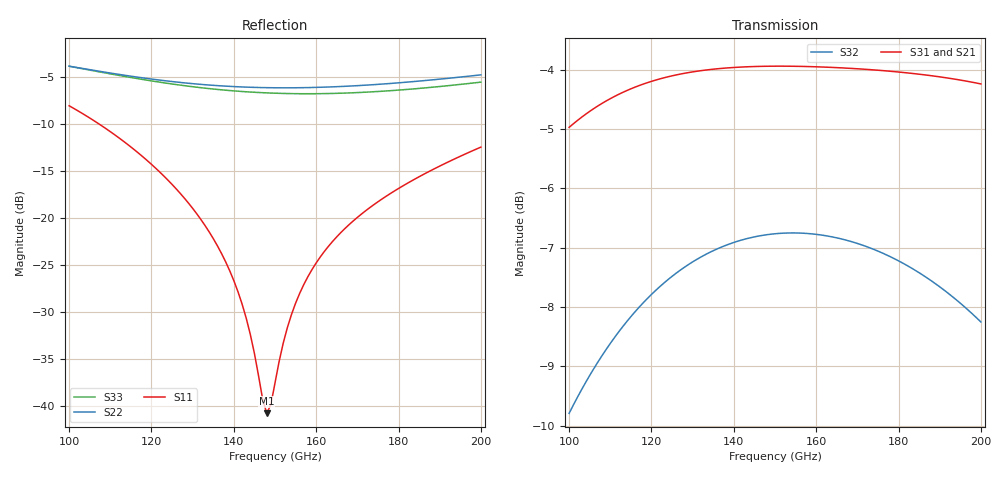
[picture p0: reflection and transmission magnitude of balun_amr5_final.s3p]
! Created with skrf 2.2.0 (http://scikit-rf.org).
# GHz S DB R 50.0
! Port[1] = P1
! Port[2] = P2
! Port[3] = P3
!freq dBS11 angS11 dBS12 angS12 dBS13 angS13
! dBS21 angS21 dBS22 angS22 dBS23 angS23
! dBS31 angS31 dBS32 angS32 dBS33 angS33
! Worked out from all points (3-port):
!   101 points, 100 GHz to 200 GHz, reference 50 ohm
!   strongest paths, dB at 100 GHz, 125 GHz, 150 GHz, 175 GHz, 200 GHz:
!     S31: -5.0, -4.1, -3.9, -4.0, -4.2
!     S21: -4.7, -4.0, -3.9, -4.2, -4.6
!     S32: -9.8, -7.5, -6.8, -7.1, -8.3
!   lowest |S11| = -40.7 dB at 148 GHz (marker M1), VSWR 1.02, Z = 50.9 - j0.104 ohm
!   |S11| at or under -10 dB: 107.2 GHz to end of sweep
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100  -8.07 129.8  -4.75 -9.9  -4.97 166.6
     -4.75 -9.9  -3.87 60.1  -9.79 91.2
     -4.97 166.6  -9.79 91.2  -3.87 50.6
120  -14.30 101.6  -4.07 -40.3  -4.20 134.6
     -4.07 -40.3  -5.23 42.3  -7.79 61.5
     -4.20 134.6  -7.79 61.5  -5.43 30.2
134  -21.46 84.0  -3.94 -59.5  -4.00 114.3
     -3.94 -59.5  -5.87 31.9  -7.08 42.4
     -4.00 114.3  -7.08 42.4  -6.25 18.3
142  -29.13 68.6  -3.93 -69.8  -3.96 103.4
     -3.93 -69.8  -6.07 26.2  -6.87 32.1
     -3.96 103.4  -6.87 32.1  -6.56 12.2
148  -40.75 -6.4  -3.94 -77.3  -3.94 95.4
     -3.94 -77.3  -6.15 21.9  -6.78 24.6
     -3.94 95.4  -6.78 24.6  -6.70 7.7
150  -37.52 -58.3  -3.95 -79.8  -3.94 92.8
     -3.95 -79.8  -6.16 20.5  -6.76 22.1
     -3.94 92.8  -6.76 22.1  -6.74 6.2
155  -29.05 -89.7  -3.98 -85.9  -3.94 86.3
     -3.98 -85.9  -6.16 16.9  -6.75 16.0
     -3.94 86.3  -6.75 16.0  -6.79 2.4
164  -22.48 -102.6  -4.04 -96.8  -3.96 74.8
     -4.04 -96.8  -6.06 10.2  -6.82 5.2
     -3.96 74.8  -6.82 5.2  -6.76 -4.3
178  -17.40 -112.7  -4.19 -113.5  -4.03 57.3
     -4.19 -113.5  -5.70 -0.9  -7.15 -11.2
     -4.03 57.3  -7.15 -11.2  -6.47 -15.3
200  -12.47 -127.8  -4.59 -140.0  -4.24 29.4
     -4.59 -140.0  -4.79 -20.2  -8.25 -37.0
     -4.24 29.4  -8.25 -37.0  -5.56 -34.2
